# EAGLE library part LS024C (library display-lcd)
LCD DISPLAY 5-character 7 segment

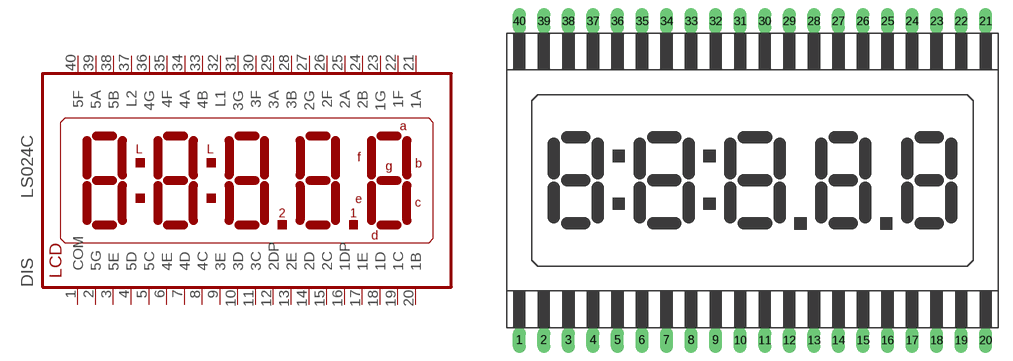
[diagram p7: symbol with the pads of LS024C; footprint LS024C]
Designator prefix DIS

## LS024C (OC_FARNELL: unknown; OC_NEWARK: unknown)  [LS024C]
1  COM  pas
2  5G  pas
3  5E  pas
4  5D  pas
5  5C  pas
6  4E  pas
7  4D  pas
8  4C  pas
9  3E  pas
10  3D  pas
11  3C  pas
12  2DP  pas
13  2E  pas
14  2D  pas
15  2C  pas
16  1DP  pas
17  1E  pas
18  1D  pas
19  1C  pas
20  1B  pas
21  1A  pas
22  1F  pas
23  1G  pas
24  2B  pas
25  2A  pas
26  2F  pas
27  2G  pas
28  3B  pas
29  3A  pas
30  3F  pas
31  3G  pas
32  L1  pas
33  4B  pas
34  4A  pas
35  4F  pas
36  4G  pas
37  L2  pas
38  5B  pas
39  5A  pas
40  5F  pas

## Footprint LS024C (pad centres in mm)
LCD DISPLAY 5-character 7 segment
drill 0.813 long: 1 -24.13,-16.51; 2 -21.59,-16.51; 3 -19.05,-16.51; 4 -16.51,-16.51; 5 -13.97,-16.51; 6 -11.43,-16.51; 7 -8.89,-16.51; 8 -6.35,-16.51; 9 -3.81,-16.51; 10 -1.27,-16.51; 11 1.27,-16.51; 12 3.81,-16.51; 13 6.35,-16.51; 14 8.89,-16.51; 15 11.43,-16.51; 16 13.97,-16.51; 17 16.51,-16.51; 18 19.05,-16.51; 19 21.59,-16.51; 20 24.13,-16.51; 21 24.13,16.51; 22 21.59,16.51; 23 19.05,16.51; 24 16.51,16.51; 25 13.97,16.51; 26 11.43,16.51; 27 8.89,16.51; 28 6.35,16.51; 29 3.81,16.51; 30 1.27,16.51; 31 -1.27,16.51; 32 -3.81,16.51; 33 -6.35,16.51; 34 -8.89,16.51; 35 -11.43,16.51; 36 -13.97,16.51; 37 -16.51,16.51; 38 -19.05,16.51; 39 -21.59,16.51; 40 -24.13,16.51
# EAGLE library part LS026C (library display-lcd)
LCD DISPLAY 8-character 7 segment

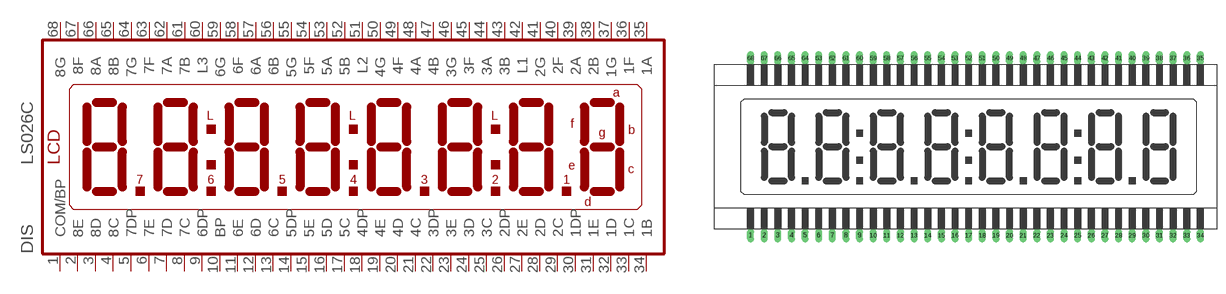
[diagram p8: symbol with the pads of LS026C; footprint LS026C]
Designator prefix DIS

## LS026C (OC_FARNELL: unknown; OC_NEWARK: unknown)  [LS026C]
1  COM/BP  pas
2  8E  pas
3  8D  pas
4  8C  pas
5  7DP  pas
6  7E  pas
7  7D  pas
8  7C  pas
9  6DP  pas
10  BP  pas
11  6E  pas
12  6D  pas
13  6C  pas
14  5DP  pas
15  5E  pas
16  5D  pas
17  5C  pas
18  4DP  pas
19  4E  pas
20  4D  pas
21  4C  pas
22  3DP  pas
23  3E  pas
24  3D  pas
25  3C  pas
26  2DP  pas
27  2E  pas
28  2D  pas
29  2C  pas
30  1DP  pas
31  1E  pas
32  1D  pas
33  1C  pas
34  1B  pas
35  1A  pas
36  1F  pas
37  1G  pas
38  2B  pas
39  2A  pas
40  2F  pas
41  2G  pas
42  L1  pas
43  3B  pas
44  3A  pas
45  3F  pas
46  3G  pas
47  4B  pas
48  4A  pas
49  4F  pas
50  4G  pas
51  L2  pas
52  5B  pas
53  5A  pas
54  5F  pas
55  5G  pas
56  6B  pas
57  6A  pas
58  6F  pas
59  6G  pas
60  L3  pas
61  7B  pas
62  7A  pas
63  7F  pas
64  7G  pas
65  8B  pas
66  8A  pas
67  8F  pas
68  8G  pas

## Footprint LS026C (pad centres in mm)
LCD DISPLAY 8-character 7 segment
drill 0.813 long: 1 -39.37,-16.51; 2 -36.83,-16.51; 3 -34.29,-16.51; 4 -31.75,-16.51; 5 -29.21,-16.51; 6 -26.67,-16.51; 7 -24.13,-16.51; 8 -21.59,-16.51; 9 -19.05,-16.51; 10 -16.51,-16.51; 11 -13.97,-16.51; 12 -11.43,-16.51; 13 -8.89,-16.51; 14 -6.35,-16.51; 15 -3.81,-16.51; 16 -1.27,-16.51; 17 1.27,-16.51; 18 3.81,-16.51; 19 6.35,-16.51; 20 8.89,-16.51; 21 11.43,-16.51; 22 13.97,-16.51; 23 16.51,-16.51; 24 19.05,-16.51; 25 21.59,-16.51; 26 24.13,-16.51; 27 26.67,-16.51; 28 29.21,-16.51; 29 31.75,-16.51; 30 34.29,-16.51; 31 36.83,-16.51; 32 39.37,-16.51; 33 41.91,-16.51; 34 44.45,-16.51; 35 44.45,16.51; 36 41.91,16.51; 37 39.37,16.51; 38 36.83,16.51; 39 34.29,16.51; 40 31.75,16.51; 41 29.21,16.51; 42 26.67,16.51; 43 24.13,16.51; 44 21.59,16.51; 45 19.05,16.51; 46 16.51,16.51; 47 13.97,16.51; 48 11.43,16.51; 49 8.89,16.51; 50 6.35,16.51; 51 3.81,16.51; 52 1.27,16.51; 53 -1.27,16.51; 54 -3.81,16.51; 55 -6.35,16.51; 56 -8.89,16.51; 57 -11.43,16.51; 58 -13.97,16.51; 59 -16.51,16.51; 60 -19.05,16.51; 61 -21.59,16.51; 62 -24.13,16.51; 63 -26.67,16.51; 64 -29.21,16.51; 65 -31.75,16.51; 66 -34.29,16.51; 67 -36.83,16.51; 68 -39.37,16.51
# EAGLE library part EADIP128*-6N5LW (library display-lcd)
LCD-GRAFIK MODUL 128x64 PIXEL EA DIP128-6N5LW BLAU-WEISS EA DIP128J-6N5LW SCHWARZ-WEISS ELECTRONIC ASSEMBLY GMBH LOCHHAMER SCHLAG 17 D-82166 GRÄFELFING Source: www.lcd-module.de .. dip128-6.pdf

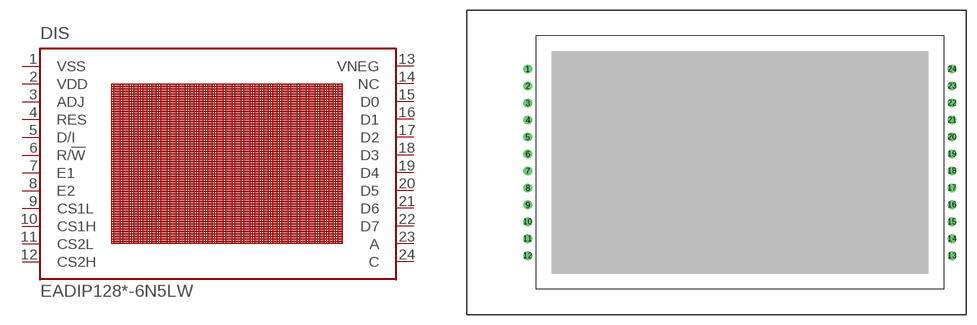
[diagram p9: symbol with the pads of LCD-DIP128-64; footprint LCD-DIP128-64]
Designator prefix DIS

## EADIP128-6N5LW (OC_FARNELL: unknown; OC_NEWARK: unknown), EADIP128J-6N5LW (OC_FARNELL: unknown; OC_NEWARK: unknown)  [LCD-DIP128-64]
1  VSS  pwr
2  VDD  pwr
3  ADJ  in
4  RES  in
5  D/I  in
6  R/!W  in
7  E1  in
8  E2  in
9  CS1L  in
10  CS1H  in
11  CS2L  in
12  CS2H  in
13  VNEG  pas
14  NC  nc
15  D0
16  D1
17  D2
18  D3
19  D4
20  D5
21  D6
22  D7
23  A  pas
24  C  pas

## Footprint LCD-DIP128-64 (pad centres in mm)
LCD-GRAFIK MODUL 128x64 PIXEL Source: www.lcd-module.de dip126-6.pdf
drill 0.8 pad 1.27 round: 1 -31.75,13.97; 2 -31.75,11.43; 3 -31.75,8.89; 4 -31.75,6.35; 5 -31.75,3.81; 6 -31.75,1.27; 7 -31.75,-1.27; 8 -31.75,-3.81; 9 -31.75,-6.35; 10 -31.75,-8.89; 11 -31.75,-11.43; 12 -31.75,-13.97; 13 31.75,-13.97; 14 31.75,-11.43; 15 31.75,-8.89; 16 31.75,-6.35; 17 31.75,-3.81; 18 31.75,-1.27; 19 31.75,1.27; 20 31.75,3.81; 21 31.75,6.35; 22 31.75,8.89; 23 31.75,11.43; 24 31.75,13.97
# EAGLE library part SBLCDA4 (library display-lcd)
LCD Display SBLCDA4 Source: http://www.softbaugh.com/downloads/SBLCDA4_Specification.pdf

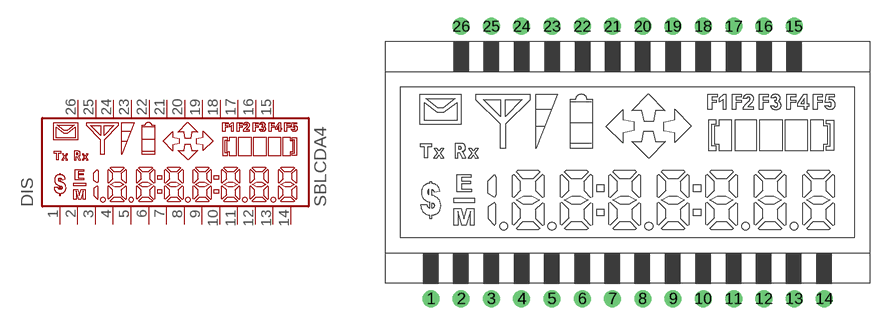
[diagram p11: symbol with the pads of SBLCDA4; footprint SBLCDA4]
Designator prefix DIS

## SBLCDA4 (OC_FARNELL: unknown; OC_NEWARK: unknown)  [SBLCDA4]
1  1  pas
2  2  pas
3  3  pas
4  4  pas
5  5  pas
6  6  pas
7  7  pas
8  8  pas
9  9  pas
10  10  pas
11  11  pas
12  12  pas
13  13  pas
14  14  pas
15  15  pas
16  16  pas
17  17  pas
18  18  pas
19  19  pas
20  20  pas
21  21  pas
22  22  pas
23  23  pas
24  24  pas
25  25  pas
26  26  pas

## Footprint SBLCDA4 (pad centres in mm)
LCD Display SBLCDA4 Source: http://www.softbaugh.com/downloads/SBLCDA4_Specification.pdf
drill 0.9 pad 1.422 round: 1 -16.51,-11.43; 2 -13.97,-11.43; 3 -11.43,-11.43; 4 -8.89,-11.43; 5 -6.35,-11.43; 6 -3.81,-11.43; 7 -1.27,-11.43; 8 1.27,-11.43; 9 3.81,-11.43; 10 6.35,-11.43; 11 8.89,-11.43; 12 11.43,-11.43; 13 13.97,-11.43; 14 16.51,-11.43; 15 13.97,11.43; 16 11.43,11.43; 17 8.89,11.43; 18 6.35,11.43; 19 3.81,11.43; 20 1.27,11.43; 21 -1.27,11.43; 22 -3.81,11.43; 23 -6.35,11.43; 24 -8.89,11.43; 25 -11.43,11.43; 26 -13.97,11.43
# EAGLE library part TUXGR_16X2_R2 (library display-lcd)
Tuxgraphics LCD display 16x2 characters reflective, without background light Source: tuxgr_12x2_r2.pdf

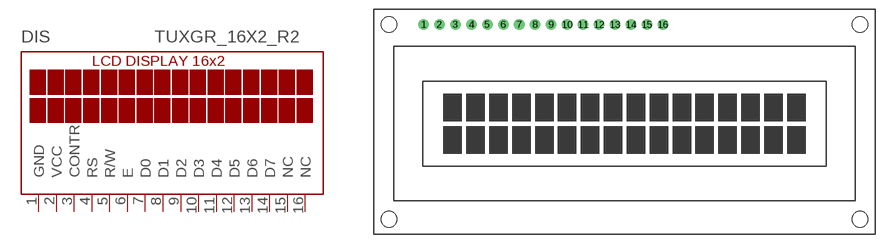
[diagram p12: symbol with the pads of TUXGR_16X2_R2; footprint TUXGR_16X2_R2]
Designator prefix DIS

## TUXGR_16X2_R2 (OC_FARNELL: unknown; OC_NEWARK: unknown)  [TUXGR_16X2_R2]
1  GND  pwr
2  VCC  pwr
3  CONTR  in
4  RS  in
5  R/W  in
6  E  in
7  D0  in
8  D1  in
9  D2  in
10  D3  in
11  D4  in
12  D5  in
13  D6  in
14  D7  in
15  NC  nc
16  NC  nc

## Footprint TUXGR_16X2_R2 (pad centres in mm)
Tuxgraphics LCD display 16x2 characters reflective, without background light Source: tuxgr_12x2_r2.pdf
drill 1 pad 1.676 round: 1 -32,15.5; 2 -29.46,15.5; 3 -26.92,15.5; 4 -24.38,15.5; 5 -21.84,15.5; 6 -19.3,15.5; 7 -16.76,15.5; 8 -14.22,15.5; 9 -11.68,15.5; 10 -9.14,15.5; 11 -6.6,15.5; 12 -4.06,15.5; 13 -1.52,15.5; 14 1.02,15.5; 15 3.56,15.5; 16 6.1,15.5
hole 2.5 at -37.5,-15.5
hole 2.5 at 37.5,-15.5
hole 2.5 at -37.5,15.5
hole 2.5 at 37.5,15.5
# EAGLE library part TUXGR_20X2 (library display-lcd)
Tuxgraphics LCD display 20x2 characters reflective, without background light Source: tuxgr_20x2.pdf

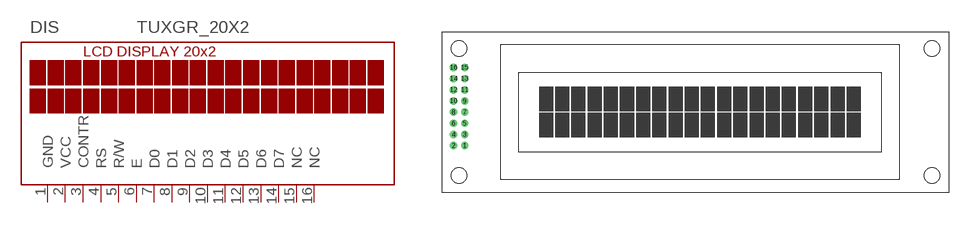
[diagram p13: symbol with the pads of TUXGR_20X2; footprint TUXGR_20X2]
Designator prefix DIS

## TUXGR_20X2 (OC_FARNELL: unknown; OC_NEWARK: unknown)  [TUXGR_20X2]
1  GND  pwr
2  VCC  pwr
3  CONTR  in
4  RS  in
5  R/W  in
6  E  in
7  D0  in
8  D1  in
9  D2  in
10  D3  in
11  D4  in
12  D5  in
13  D6  in
14  D7  in
15  NC  nc
16  NC  nc

## Footprint TUXGR_20X2 (pad centres in mm)
Tuxgraphics LCD display 20x2 characters reflective, without background light Source: tuxgr_20x2.pdf
drill 1 pad 1.676 round: 1 -52.73,-7.62; 2 -55.27,-7.62; 3 -52.73,-5.08; 4 -55.27,-5.08; 5 -52.73,-2.54; 6 -55.27,-2.54; 7 -52.73,0; 8 -55.27,0; 9 -52.73,2.54; 10 -55.27,2.54; 11 -52.73,5.08; 12 -55.27,5.08; 13 -52.73,7.62; 14 -55.27,7.62; 15 -52.73,10.16; 16 -55.27,10.16
hole 3.5 at -54,-14.5
hole 3.5 at 54,-14.5
hole 3.5 at -54,14.5
hole 3.5 at 54,14.5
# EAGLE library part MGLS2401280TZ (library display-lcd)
LCD Display 240 x 128 Dots Source: VARITRONIX LIMITED .. LCD_f1187192714.pdf

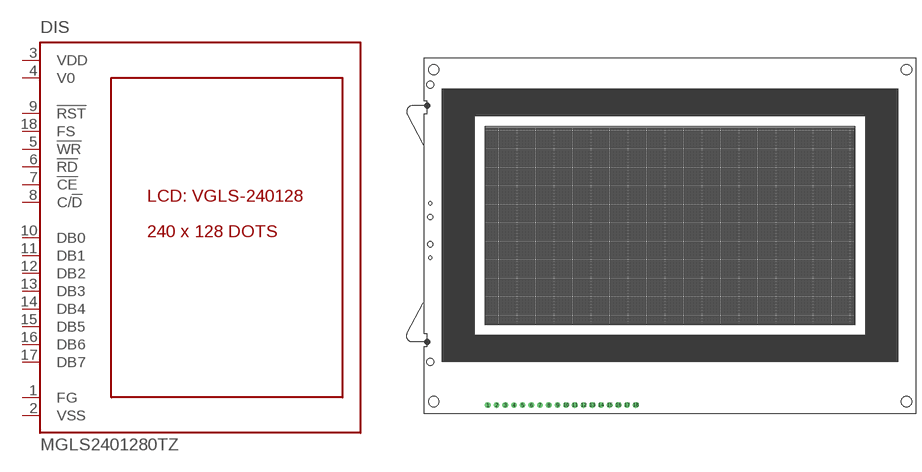
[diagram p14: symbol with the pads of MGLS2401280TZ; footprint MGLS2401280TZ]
Designator prefix DIS

## MGLS2401280TZ (OC_FARNELL: 1183196; OC_NEWARK: unknown)  [MGLS2401280TZ]
1  FG  in
2  VSS  in
3  VDD  in
4  V0  in
5  !WR  in
6  !RD  in
7  !CE  in
8  C/!D  in
9  !RST  in
10  DB0
11  DB1
12  DB2
13  DB3
14  DB4
15  DB5
16  DB6
17  DB7
18  FS  in

## Footprint MGLS2401280TZ (pad centres in mm)
LCD Display 240 x 128 Dots Source: VARITRONIX LIMITED .. LCD_f1187192714.pdf
drill 1 pad 1.676 round: 1 15.8,-1; 2 18.34,-1; 3 20.88,-1; 4 23.42,-1; 5 25.96,-1; 6 28.5,-1; 7 31.04,-1; 8 33.58,-1; 9 36.12,-1; 10 38.66,-1; 11 41.2,-1; 12 43.74,-1; 13 46.28,-1; 14 48.82,-1; 15 51.36,-1; 16 53.9,-1; 17 56.44,-1; 18 58.98,-1
hole 3 at 0,0
hole 3 at 138,0
hole 3 at 0,97
hole 3 at 138,97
